VERSION 5.7 ;
BUSBITCHARS "[]" ;
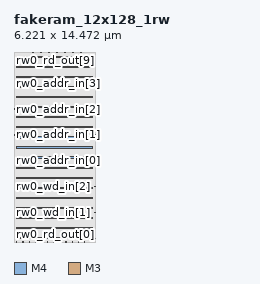
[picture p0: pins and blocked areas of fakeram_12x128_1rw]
MACRO fakeram_12x128_1rw
  FOREIGN fakeram_12x128_1rw 0 0 ;
  SYMMETRY X Y R90 ;
  SIZE 6.221 BY 14.472 ;
  CLASS BLOCK ;
  PIN rw0_wd_in[0]
    DIRECTION INPUT ;
    USE SIGNAL ;
    SHAPE ABUTMENT ;
    PORT
      LAYER M4 ;
      RECT 0.000 0.276 0.072 0.300 ;
    END
  END rw0_wd_in[0]
  PIN rw0_wd_in[1]
    DIRECTION INPUT ;
    USE SIGNAL ;
    SHAPE ABUTMENT ;
    PORT
      LAYER M4 ;
      RECT 0.000 2.244 0.072 2.268 ;
    END
  END rw0_wd_in[1]
  PIN rw0_wd_in[2]
    DIRECTION INPUT ;
    USE SIGNAL ;
    SHAPE ABUTMENT ;
    PORT
      LAYER M4 ;
      RECT 0.000 4.212 0.072 4.236 ;
    END
  END rw0_wd_in[2]
  PIN rw0_wd_in[3]
    DIRECTION INPUT ;
    USE SIGNAL ;
    SHAPE ABUTMENT ;
    PORT
      LAYER M4 ;
      RECT 6.149 0.276 6.221 0.300 ;
    END
  END rw0_wd_in[3]
  PIN rw0_wd_in[4]
    DIRECTION INPUT ;
    USE SIGNAL ;
    SHAPE ABUTMENT ;
    PORT
      LAYER M4 ;
      RECT 6.149 2.244 6.221 2.268 ;
    END
  END rw0_wd_in[4]
  PIN rw0_wd_in[5]
    DIRECTION INPUT ;
    USE SIGNAL ;
    SHAPE ABUTMENT ;
    PORT
      LAYER M4 ;
      RECT 6.149 4.212 6.221 4.236 ;
    END
  END rw0_wd_in[5]
  PIN rw0_wd_in[6]
    DIRECTION OUTPUT ;
    USE SIGNAL ;
    SHAPE ABUTMENT ;
    PORT
      LAYER M3 ;
      RECT 0.207 0.000 0.225 0.054 ;
    END
  END rw0_wd_in[6]
  PIN rw0_wd_in[7]
    DIRECTION OUTPUT ;
    USE SIGNAL ;
    SHAPE ABUTMENT ;
    PORT
      LAYER M3 ;
      RECT 0.675 0.000 0.693 0.054 ;
    END
  END rw0_wd_in[7]
  PIN rw0_wd_in[8]
    DIRECTION OUTPUT ;
    USE SIGNAL ;
    SHAPE ABUTMENT ;
    PORT
      LAYER M3 ;
      RECT 1.143 0.000 1.161 0.054 ;
    END
  END rw0_wd_in[8]
  PIN rw0_wd_in[9]
    DIRECTION OUTPUT ;
    USE SIGNAL ;
    SHAPE ABUTMENT ;
    PORT
      LAYER M3 ;
      RECT 1.611 0.000 1.629 0.054 ;
    END
  END rw0_wd_in[9]
  PIN rw0_wd_in[10]
    DIRECTION OUTPUT ;
    USE SIGNAL ;
    SHAPE ABUTMENT ;
    PORT
      LAYER M3 ;
      RECT 2.079 0.000 2.097 0.054 ;
    END
  END rw0_wd_in[10]
  PIN rw0_wd_in[11]
    DIRECTION OUTPUT ;
    USE SIGNAL ;
    SHAPE ABUTMENT ;
    PORT
      LAYER M3 ;
      RECT 2.547 0.000 2.565 0.054 ;
    END
  END rw0_wd_in[11]
  PIN rw0_rd_out[0]
    DIRECTION OUTPUT ;
    USE SIGNAL ;
    SHAPE ABUTMENT ;
    PORT
      LAYER M3 ;
      RECT 3.015 0.000 3.033 0.054 ;
    END
  END rw0_rd_out[0]
  PIN rw0_rd_out[1]
    DIRECTION OUTPUT ;
    USE SIGNAL ;
    SHAPE ABUTMENT ;
    PORT
      LAYER M3 ;
      RECT 3.483 0.000 3.501 0.054 ;
    END
  END rw0_rd_out[1]
  PIN rw0_rd_out[2]
    DIRECTION OUTPUT ;
    USE SIGNAL ;
    SHAPE ABUTMENT ;
    PORT
      LAYER M3 ;
      RECT 3.951 0.000 3.969 0.054 ;
    END
  END rw0_rd_out[2]
  PIN rw0_rd_out[3]
    DIRECTION OUTPUT ;
    USE SIGNAL ;
    SHAPE ABUTMENT ;
    PORT
      LAYER M3 ;
      RECT 4.419 0.000 4.437 0.054 ;
    END
  END rw0_rd_out[3]
  PIN rw0_rd_out[4]
    DIRECTION OUTPUT ;
    USE SIGNAL ;
    SHAPE ABUTMENT ;
    PORT
      LAYER M3 ;
      RECT 4.887 0.000 4.905 0.054 ;
    END
  END rw0_rd_out[4]
  PIN rw0_rd_out[5]
    DIRECTION OUTPUT ;
    USE SIGNAL ;
    SHAPE ABUTMENT ;
    PORT
      LAYER M3 ;
      RECT 5.355 0.000 5.373 0.054 ;
    END
  END rw0_rd_out[5]
  PIN rw0_rd_out[6]
    DIRECTION OUTPUT ;
    USE SIGNAL ;
    SHAPE ABUTMENT ;
    PORT
      LAYER M3 ;
      RECT 0.207 14.418 0.225 14.472 ;
    END
  END rw0_rd_out[6]
  PIN rw0_rd_out[7]
    DIRECTION OUTPUT ;
    USE SIGNAL ;
    SHAPE ABUTMENT ;
    PORT
      LAYER M3 ;
      RECT 0.819 14.418 0.837 14.472 ;
    END
  END rw0_rd_out[7]
  PIN rw0_rd_out[8]
    DIRECTION OUTPUT ;
    USE SIGNAL ;
    SHAPE ABUTMENT ;
    PORT
      LAYER M3 ;
      RECT 1.431 14.418 1.449 14.472 ;
    END
  END rw0_rd_out[8]
  PIN rw0_rd_out[9]
    DIRECTION OUTPUT ;
    USE SIGNAL ;
    SHAPE ABUTMENT ;
    PORT
      LAYER M3 ;
      RECT 2.043 14.418 2.061 14.472 ;
    END
  END rw0_rd_out[9]
  PIN rw0_rd_out[10]
    DIRECTION OUTPUT ;
    USE SIGNAL ;
    SHAPE ABUTMENT ;
    PORT
      LAYER M3 ;
      RECT 2.655 14.418 2.673 14.472 ;
    END
  END rw0_rd_out[10]
  PIN rw0_rd_out[11]
    DIRECTION OUTPUT ;
    USE SIGNAL ;
    SHAPE ABUTMENT ;
    PORT
      LAYER M3 ;
      RECT 3.267 14.418 3.285 14.472 ;
    END
  END rw0_rd_out[11]
  PIN rw0_addr_in[0]
    DIRECTION INPUT ;
    USE SIGNAL ;
    SHAPE ABUTMENT ;
    PORT
      LAYER M4 ;
      RECT 0.000 6.180 0.072 6.204 ;
    END
  END rw0_addr_in[0]
  PIN rw0_addr_in[1]
    DIRECTION INPUT ;
    USE SIGNAL ;
    SHAPE ABUTMENT ;
    PORT
      LAYER M4 ;
      RECT 0.000 8.148 0.072 8.172 ;
    END
  END rw0_addr_in[1]
  PIN rw0_addr_in[2]
    DIRECTION INPUT ;
    USE SIGNAL ;
    SHAPE ABUTMENT ;
    PORT
      LAYER M4 ;
      RECT 0.000 10.116 0.072 10.140 ;
    END
  END rw0_addr_in[2]
  PIN rw0_addr_in[3]
    DIRECTION INPUT ;
    USE SIGNAL ;
    SHAPE ABUTMENT ;
    PORT
      LAYER M4 ;
      RECT 0.000 12.084 0.072 12.108 ;
    END
  END rw0_addr_in[3]
  PIN rw0_addr_in[4]
    DIRECTION INPUT ;
    USE SIGNAL ;
    SHAPE ABUTMENT ;
    PORT
      LAYER M4 ;
      RECT 6.149 6.180 6.221 6.204 ;
    END
  END rw0_addr_in[4]
  PIN rw0_addr_in[5]
    DIRECTION INPUT ;
    USE SIGNAL ;
    SHAPE ABUTMENT ;
    PORT
      LAYER M4 ;
      RECT 6.149 8.148 6.221 8.172 ;
    END
  END rw0_addr_in[5]
  PIN rw0_addr_in[6]
    DIRECTION INPUT ;
    USE SIGNAL ;
    SHAPE ABUTMENT ;
    PORT
      LAYER M4 ;
      RECT 6.149 10.116 6.221 10.140 ;
    END
  END rw0_addr_in[6]
  PIN rw0_we_in
    DIRECTION INPUT ;
    USE SIGNAL ;
    SHAPE ABUTMENT ;
    PORT
      LAYER M3 ;
      RECT 3.879 14.418 3.897 14.472 ;
    END
  END rw0_we_in
  PIN rw0_ce_in
    DIRECTION INPUT ;
    USE SIGNAL ;
    SHAPE ABUTMENT ;
    PORT
      LAYER M3 ;
      RECT 4.491 14.418 4.509 14.472 ;
    END
  END rw0_ce_in
  PIN rw0_clk
    DIRECTION INPUT ;
    USE SIGNAL ;
    SHAPE ABUTMENT ;
    PORT
      LAYER M3 ;
      RECT 5.103 14.418 5.121 14.472 ;
    END
  END rw0_clk
  PIN VSS
    DIRECTION INOUT ;
    USE GROUND ;
    PORT
      LAYER M4 ;
      RECT 0.216 0.240 6.005 0.336 ;
      RECT 0.216 1.008 6.005 1.104 ;
      RECT 0.216 1.776 6.005 1.872 ;
      RECT 0.216 2.544 6.005 2.640 ;
      RECT 0.216 3.312 6.005 3.408 ;
      RECT 0.216 4.080 6.005 4.176 ;
      RECT 0.216 4.848 6.005 4.944 ;
      RECT 0.216 5.616 6.005 5.712 ;
      RECT 0.216 6.384 6.005 6.480 ;
      RECT 0.216 7.152 6.005 7.248 ;
      RECT 0.216 7.920 6.005 8.016 ;
      RECT 0.216 8.688 6.005 8.784 ;
      RECT 0.216 9.456 6.005 9.552 ;
      RECT 0.216 10.224 6.005 10.320 ;
      RECT 0.216 10.992 6.005 11.088 ;
      RECT 0.216 11.760 6.005 11.856 ;
      RECT 0.216 12.528 6.005 12.624 ;
      RECT 0.216 13.296 6.005 13.392 ;
      RECT 0.216 14.064 6.005 14.160 ;
    END
  END VSS
  PIN VDD
    DIRECTION INOUT ;
    USE POWER ;
    PORT
      LAYER M4 ;
      RECT 0.216 0.240 6.005 0.336 ;
      RECT 0.216 1.008 6.005 1.104 ;
      RECT 0.216 1.776 6.005 1.872 ;
      RECT 0.216 2.544 6.005 2.640 ;
      RECT 0.216 3.312 6.005 3.408 ;
      RECT 0.216 4.080 6.005 4.176 ;
      RECT 0.216 4.848 6.005 4.944 ;
      RECT 0.216 5.616 6.005 5.712 ;
      RECT 0.216 6.384 6.005 6.480 ;
      RECT 0.216 7.152 6.005 7.248 ;
      RECT 0.216 7.920 6.005 8.016 ;
      RECT 0.216 8.688 6.005 8.784 ;
      RECT 0.216 9.456 6.005 9.552 ;
      RECT 0.216 10.224 6.005 10.320 ;
      RECT 0.216 10.992 6.005 11.088 ;
      RECT 0.216 11.760 6.005 11.856 ;
      RECT 0.216 12.528 6.005 12.624 ;
      RECT 0.216 13.296 6.005 13.392 ;
      RECT 0.216 14.064 6.005 14.160 ;
    END
  END VDD
  OBS
    LAYER M1 ;
    RECT 0 0 6.221 14.472 ;
    LAYER M2 ;
    RECT 0 0 6.221 14.472 ;
    LAYER M3 ;
    RECT 0 0 6.221 14.472 ;
    LAYER M4 ;
    RECT 0 0 6.221 14.472 ;
  END
END fakeram_12x128_1rw

END LIBRARY
